VERSION 5.7 ;
  NOWIREEXTENSIONATPIN ON ;
  DIVIDERCHAR "/" ;
  BUSBITCHARS "[]" ;
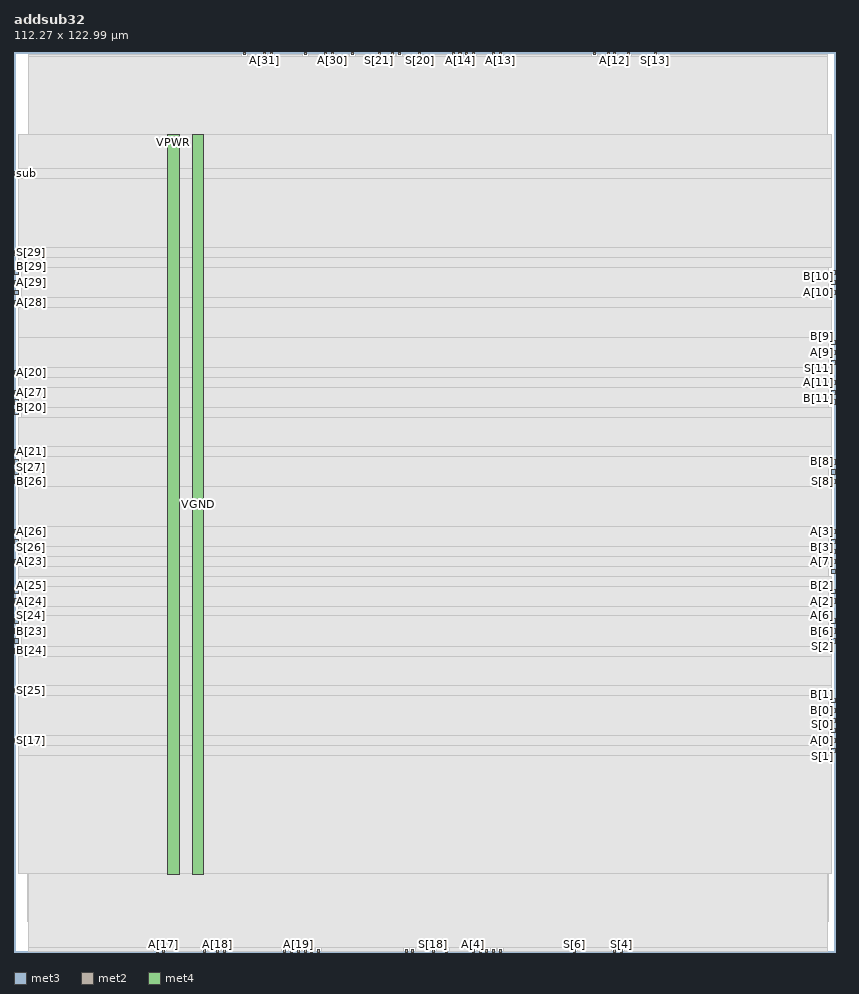
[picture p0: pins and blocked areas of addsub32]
MACRO addsub32
  CLASS BLOCK ;
  FOREIGN addsub32 ;
  ORIGIN 0.000 0.000 ;
  SIZE 112.270 BY 122.990 ;
  PIN A[0]
    DIRECTION INPUT ;
    USE SIGNAL ;
    ANTENNAGATEAREA 0.159000 ;
    PORT
      LAYER met3 ;
        RECT 111.670 28.600 112.270 29.200 ;
    END
  END A[0]
  PIN A[10]
    DIRECTION INPUT ;
    USE SIGNAL ;
    ANTENNAGATEAREA 0.213000 ;
    PORT
      LAYER met3 ;
        RECT 111.670 89.800 112.270 90.400 ;
    END
  END A[10]
  PIN A[11]
    DIRECTION INPUT ;
    USE SIGNAL ;
    ANTENNAGATEAREA 0.213000 ;
    PORT
      LAYER met3 ;
        RECT 111.670 77.560 112.270 78.160 ;
    END
  END A[11]
  PIN A[12]
    DIRECTION INPUT ;
    USE SIGNAL ;
    ANTENNAGATEAREA 0.495000 ;
    PORT
      LAYER met2 ;
        RECT 81.970 122.710 82.250 122.990 ;
    END
  END A[12]
  PIN A[13]
    DIRECTION INPUT ;
    USE SIGNAL ;
    ANTENNAGATEAREA 0.213000 ;
    PORT
      LAYER met2 ;
        RECT 66.330 122.710 66.610 122.990 ;
    END
  END A[13]
  PIN A[14]
    DIRECTION INPUT ;
    USE SIGNAL ;
    ANTENNAGATEAREA 0.213000 ;
    PORT
      LAYER met2 ;
        RECT 60.810 122.710 61.090 122.990 ;
    END
  END A[14]
  PIN A[15]
    DIRECTION INPUT ;
    USE SIGNAL ;
    ANTENNAGATEAREA 0.247500 ;
    PORT
      LAYER met2 ;
        RECT 62.650 122.710 62.930 122.990 ;
    END
  END A[15]
  PIN A[16]
    DIRECTION INPUT ;
    USE SIGNAL ;
    ANTENNAGATEAREA 0.213000 ;
    PORT
      LAYER met2 ;
        RECT 28.610 0.000 28.890 0.280 ;
    END
  END A[16]
  PIN A[17]
    DIRECTION INPUT ;
    USE SIGNAL ;
    ANTENNAGATEAREA 0.126000 ;
    PORT
      LAYER met2 ;
        RECT 20.330 0.000 20.610 0.280 ;
    END
  END A[17]
  PIN A[18]
    DIRECTION INPUT ;
    USE SIGNAL ;
    ANTENNAGATEAREA 0.213000 ;
    PORT
      LAYER met2 ;
        RECT 27.690 0.000 27.970 0.280 ;
    END
  END A[18]
  PIN A[19]
    DIRECTION INPUT ;
    USE SIGNAL ;
    ANTENNAGATEAREA 0.213000 ;
    PORT
      LAYER met2 ;
        RECT 38.730 0.000 39.010 0.280 ;
    END
  END A[19]
  PIN A[1]
    DIRECTION INPUT ;
    USE SIGNAL ;
    ANTENNAGATEAREA 0.126000 ;
    PORT
      LAYER met3 ;
        RECT 111.670 31.320 112.270 31.920 ;
    END
  END A[1]
  PIN A[20]
    DIRECTION INPUT ;
    USE SIGNAL ;
    ANTENNAGATEAREA 0.126000 ;
    PORT
      LAYER met3 ;
        RECT 0.000 78.920 0.600 79.520 ;
    END
  END A[20]
  PIN A[21]
    DIRECTION INPUT ;
    USE SIGNAL ;
    ANTENNAGATEAREA 0.213000 ;
    PORT
      LAYER met3 ;
        RECT 0.000 68.040 0.600 68.640 ;
    END
  END A[21]
  PIN A[22]
    DIRECTION INPUT ;
    USE SIGNAL ;
    ANTENNAGATEAREA 0.213000 ;
    PORT
      LAYER met2 ;
        RECT 39.650 0.000 39.930 0.280 ;
    END
  END A[22]
  PIN A[23]
    DIRECTION INPUT ;
    USE SIGNAL ;
    ANTENNAGATEAREA 0.213000 ;
    PORT
      LAYER met3 ;
        RECT 0.000 53.080 0.600 53.680 ;
    END
  END A[23]
  PIN A[24]
    DIRECTION INPUT ;
    USE SIGNAL ;
    ANTENNAGATEAREA 0.213000 ;
    PORT
      LAYER met3 ;
        RECT 0.000 47.640 0.600 48.240 ;
    END
  END A[24]
  PIN A[25]
    DIRECTION INPUT ;
    USE SIGNAL ;
    ANTENNAGATEAREA 0.126000 ;
    PORT
      LAYER met3 ;
        RECT 0.000 49.000 0.600 49.600 ;
    END
  END A[25]
  PIN A[26]
    DIRECTION INPUT ;
    USE SIGNAL ;
    ANTENNAGATEAREA 0.213000 ;
    PORT
      LAYER met3 ;
        RECT 0.000 57.160 0.600 57.760 ;
    END
  END A[26]
  PIN A[27]
    DIRECTION INPUT ;
    USE SIGNAL ;
    ANTENNAGATEAREA 0.213000 ;
    PORT
      LAYER met3 ;
        RECT 0.000 76.200 0.600 76.800 ;
    END
  END A[27]
  PIN A[28]
    DIRECTION INPUT ;
    USE SIGNAL ;
    ANTENNAGATEAREA 0.213000 ;
    PORT
      LAYER met3 ;
        RECT 0.000 88.440 0.600 89.040 ;
    END
  END A[28]
  PIN A[29]
    DIRECTION INPUT ;
    USE SIGNAL ;
    ANTENNAGATEAREA 0.213000 ;
    PORT
      LAYER met3 ;
        RECT 0.000 91.160 0.600 91.760 ;
    END
  END A[29]
  PIN A[2]
    DIRECTION INPUT ;
    USE SIGNAL ;
    ANTENNAGATEAREA 0.213000 ;
    PORT
      LAYER met3 ;
        RECT 111.670 47.640 112.270 48.240 ;
    END
  END A[2]
  PIN A[30]
    DIRECTION INPUT ;
    USE SIGNAL ;
    ANTENNAGATEAREA 0.213000 ;
    PORT
      LAYER met2 ;
        RECT 43.330 122.710 43.610 122.990 ;
    END
  END A[30]
  PIN A[31]
    DIRECTION INPUT ;
    USE SIGNAL ;
    ANTENNAGATEAREA 0.213000 ;
    PORT
      LAYER met2 ;
        RECT 34.130 122.710 34.410 122.990 ;
    END
  END A[31]
  PIN A[3]
    DIRECTION INPUT ;
    USE SIGNAL ;
    ANTENNAGATEAREA 0.213000 ;
    PORT
      LAYER met3 ;
        RECT 111.670 57.160 112.270 57.760 ;
    END
  END A[3]
  PIN A[4]
    DIRECTION INPUT ;
    USE SIGNAL ;
    ANTENNAGATEAREA 0.213000 ;
    PORT
      LAYER met2 ;
        RECT 62.650 0.000 62.930 0.280 ;
    END
  END A[4]
  PIN A[5]
    DIRECTION INPUT ;
    USE SIGNAL ;
    ANTENNAGATEAREA 0.247500 ;
    PORT
      LAYER met2 ;
        RECT 64.490 0.000 64.770 0.280 ;
    END
  END A[5]
  PIN A[6]
    DIRECTION INPUT ;
    USE SIGNAL ;
    ANTENNAGATEAREA 0.126000 ;
    PORT
      LAYER met3 ;
        RECT 111.670 44.920 112.270 45.520 ;
    END
  END A[6]
  PIN A[7]
    DIRECTION INPUT ;
    USE SIGNAL ;
    ANTENNAGATEAREA 0.213000 ;
    PORT
      LAYER met3 ;
        RECT 111.670 53.080 112.270 53.680 ;
    END
  END A[7]
  PIN A[8]
    DIRECTION INPUT ;
    USE SIGNAL ;
    ANTENNAGATEAREA 0.213000 ;
    PORT
      LAYER met3 ;
        RECT 111.670 65.320 112.270 65.920 ;
    END
  END A[8]
  PIN A[9]
    DIRECTION INPUT ;
    USE SIGNAL ;
    ANTENNAGATEAREA 0.495000 ;
    PORT
      LAYER met3 ;
        RECT 111.670 81.640 112.270 82.240 ;
    END
  END A[9]
  PIN B[0]
    DIRECTION INPUT ;
    USE SIGNAL ;
    ANTENNAGATEAREA 0.247500 ;
    PORT
      LAYER met3 ;
        RECT 111.670 32.680 112.270 33.280 ;
    END
  END B[0]
  PIN B[10]
    DIRECTION INPUT ;
    USE SIGNAL ;
    ANTENNAGATEAREA 0.247500 ;
    PORT
      LAYER met3 ;
        RECT 111.670 91.160 112.270 91.760 ;
    END
  END B[10]
  PIN B[11]
    DIRECTION INPUT ;
    USE SIGNAL ;
    ANTENNAGATEAREA 0.213000 ;
    PORT
      LAYER met3 ;
        RECT 111.670 76.200 112.270 76.800 ;
    END
  END B[11]
  PIN B[12]
    DIRECTION INPUT ;
    USE SIGNAL ;
    ANTENNAGATEAREA 0.495000 ;
    PORT
      LAYER met2 ;
        RECT 81.050 122.710 81.330 122.990 ;
    END
  END B[12]
  PIN B[13]
    DIRECTION INPUT ;
    USE SIGNAL ;
    ANTENNAGATEAREA 0.247500 ;
    PORT
      LAYER met2 ;
        RECT 65.410 122.710 65.690 122.990 ;
    END
  END B[13]
  PIN B[14]
    DIRECTION INPUT ;
    USE SIGNAL ;
    ANTENNAGATEAREA 0.213000 ;
    PORT
      LAYER met2 ;
        RECT 59.890 122.710 60.170 122.990 ;
    END
  END B[14]
  PIN B[15]
    DIRECTION INPUT ;
    USE SIGNAL ;
    ANTENNAGATEAREA 0.247500 ;
    PORT
      LAYER met2 ;
        RECT 61.730 122.710 62.010 122.990 ;
    END
  END B[15]
  PIN B[16]
    DIRECTION INPUT ;
    USE SIGNAL ;
    ANTENNAGATEAREA 0.213000 ;
    PORT
      LAYER met2 ;
        RECT 25.850 0.000 26.130 0.280 ;
    END
  END B[16]
  PIN B[17]
    DIRECTION INPUT ;
    USE SIGNAL ;
    ANTENNAGATEAREA 0.126000 ;
    PORT
      LAYER met2 ;
        RECT 19.410 0.000 19.690 0.280 ;
    END
  END B[17]
  PIN B[18]
    DIRECTION INPUT ;
    USE SIGNAL ;
    ANTENNAGATEAREA 0.213000 ;
    PORT
      LAYER met2 ;
        RECT 37.810 0.000 38.090 0.280 ;
    END
  END B[18]
  PIN B[19]
    DIRECTION INPUT ;
    USE SIGNAL ;
    ANTENNAGATEAREA 0.213000 ;
    PORT
      LAYER met2 ;
        RECT 40.570 0.000 40.850 0.280 ;
    END
  END B[19]
  PIN B[1]
    DIRECTION INPUT ;
    USE SIGNAL ;
    ANTENNAGATEAREA 0.213000 ;
    PORT
      LAYER met3 ;
        RECT 111.670 34.040 112.270 34.640 ;
    END
  END B[1]
  PIN B[20]
    DIRECTION INPUT ;
    USE SIGNAL ;
    ANTENNAGATEAREA 0.126000 ;
    PORT
      LAYER met3 ;
        RECT 0.000 74.840 0.600 75.440 ;
    END
  END B[20]
  PIN B[21]
    DIRECTION INPUT ;
    USE SIGNAL ;
    ANTENNAGATEAREA 0.213000 ;
    PORT
      LAYER met3 ;
        RECT 0.000 65.320 0.600 65.920 ;
    END
  END B[21]
  PIN B[22]
    DIRECTION INPUT ;
    USE SIGNAL ;
    ANTENNAGATEAREA 0.213000 ;
    PORT
      LAYER met2 ;
        RECT 41.490 0.000 41.770 0.280 ;
    END
  END B[22]
  PIN B[23]
    DIRECTION INPUT ;
    USE SIGNAL ;
    ANTENNAGATEAREA 0.213000 ;
    PORT
      LAYER met3 ;
        RECT 0.000 43.560 0.600 44.160 ;
    END
  END B[23]
  PIN B[24]
    DIRECTION INPUT ;
    USE SIGNAL ;
    ANTENNAGATEAREA 0.213000 ;
    PORT
      LAYER met3 ;
        RECT 0.000 40.840 0.600 41.440 ;
    END
  END B[24]
  PIN B[25]
    DIRECTION INPUT ;
    USE SIGNAL ;
    ANTENNAGATEAREA 0.126000 ;
    PORT
      LAYER met3 ;
        RECT 0.000 42.200 0.600 42.800 ;
    END
  END B[25]
  PIN B[26]
    DIRECTION INPUT ;
    USE SIGNAL ;
    ANTENNAGATEAREA 0.213000 ;
    PORT
      LAYER met3 ;
        RECT 0.000 63.960 0.600 64.560 ;
    END
  END B[26]
  PIN B[27]
    DIRECTION INPUT ;
    USE SIGNAL ;
    ANTENNAGATEAREA 0.213000 ;
    PORT
      LAYER met3 ;
        RECT 0.000 73.480 0.600 74.080 ;
    END
  END B[27]
  PIN B[28]
    DIRECTION INPUT ;
    USE SIGNAL ;
    ANTENNAGATEAREA 0.213000 ;
    PORT
      LAYER met3 ;
        RECT 0.000 89.800 0.600 90.400 ;
    END
  END B[28]
  PIN B[29]
    DIRECTION INPUT ;
    USE SIGNAL ;
    ANTENNAGATEAREA 0.213000 ;
    PORT
      LAYER met3 ;
        RECT 0.000 92.520 0.600 93.120 ;
    END
  END B[29]
  PIN B[2]
    DIRECTION INPUT ;
    USE SIGNAL ;
    ANTENNAGATEAREA 0.126000 ;
    PORT
      LAYER met3 ;
        RECT 111.670 49.000 112.270 49.600 ;
    END
  END B[2]
  PIN B[30]
    DIRECTION INPUT ;
    USE SIGNAL ;
    ANTENNAGATEAREA 0.213000 ;
    PORT
      LAYER met2 ;
        RECT 42.410 122.710 42.690 122.990 ;
    END
  END B[30]
  PIN B[31]
    DIRECTION INPUT ;
    USE SIGNAL ;
    ANTENNAGATEAREA 0.213000 ;
    PORT
      LAYER met2 ;
        RECT 35.050 122.710 35.330 122.990 ;
    END
  END B[31]
  PIN B[3]
    DIRECTION INPUT ;
    USE SIGNAL ;
    ANTENNAGATEAREA 0.126000 ;
    PORT
      LAYER met3 ;
        RECT 111.670 55.800 112.270 56.400 ;
    END
  END B[3]
  PIN B[4]
    DIRECTION INPUT ;
    USE SIGNAL ;
    ANTENNAGATEAREA 0.213000 ;
    PORT
      LAYER met2 ;
        RECT 63.570 0.000 63.850 0.280 ;
    END
  END B[4]
  PIN B[5]
    DIRECTION INPUT ;
    USE SIGNAL ;
    ANTENNAGATEAREA 0.213000 ;
    PORT
      LAYER met2 ;
        RECT 66.330 0.000 66.610 0.280 ;
    END
  END B[5]
  PIN B[6]
    DIRECTION INPUT ;
    USE SIGNAL ;
    ANTENNAGATEAREA 0.126000 ;
    PORT
      LAYER met3 ;
        RECT 111.670 43.560 112.270 44.160 ;
    END
  END B[6]
  PIN B[7]
    DIRECTION INPUT ;
    USE SIGNAL ;
    ANTENNAGATEAREA 0.213000 ;
    PORT
      LAYER met3 ;
        RECT 111.670 51.720 112.270 52.320 ;
    END
  END B[7]
  PIN B[8]
    DIRECTION INPUT ;
    USE SIGNAL ;
    ANTENNAGATEAREA 0.126000 ;
    PORT
      LAYER met3 ;
        RECT 111.670 66.680 112.270 67.280 ;
    END
  END B[8]
  PIN B[9]
    DIRECTION INPUT ;
    USE SIGNAL ;
    ANTENNAGATEAREA 0.495000 ;
    PORT
      LAYER met3 ;
        RECT 111.670 83.000 112.270 83.600 ;
    END
  END B[9]
  PIN S[0]
    DIRECTION OUTPUT ;
    USE SIGNAL ;
    ANTENNADIFFAREA 0.702900 ;
    PORT
      LAYER met3 ;
        RECT 111.670 29.960 112.270 30.560 ;
    END
  END S[0]
  PIN S[10]
    DIRECTION OUTPUT ;
    USE SIGNAL ;
    ANTENNADIFFAREA 1.336500 ;
    PORT
      LAYER met3 ;
        RECT 111.670 92.520 112.270 93.120 ;
    END
  END S[10]
  PIN S[11]
    DIRECTION OUTPUT ;
    USE SIGNAL ;
    ANTENNADIFFAREA 1.336500 ;
    PORT
      LAYER met3 ;
        RECT 111.670 80.280 112.270 80.880 ;
    END
  END S[11]
  PIN S[12]
    DIRECTION OUTPUT ;
    USE SIGNAL ;
    ANTENNADIFFAREA 1.336500 ;
    PORT
      LAYER met2 ;
        RECT 83.810 122.710 84.090 122.990 ;
    END
  END S[12]
  PIN S[13]
    DIRECTION OUTPUT ;
    USE SIGNAL ;
    ANTENNAGATEAREA 0.126000 ;
    ANTENNADIFFAREA 0.429000 ;
    PORT
      LAYER met2 ;
        RECT 87.490 122.710 87.770 122.990 ;
    END
  END S[13]
  PIN S[14]
    DIRECTION OUTPUT ;
    USE SIGNAL ;
    ANTENNADIFFAREA 1.336500 ;
    PORT
      LAYER met2 ;
        RECT 79.210 122.710 79.490 122.990 ;
    END
  END S[14]
  PIN S[15]
    DIRECTION OUTPUT ;
    USE SIGNAL ;
    ANTENNADIFFAREA 1.336500 ;
    PORT
      LAYER met2 ;
        RECT 52.530 122.710 52.810 122.990 ;
    END
  END S[15]
  PIN S[16]
    DIRECTION OUTPUT ;
    USE SIGNAL ;
    ANTENNADIFFAREA 1.336500 ;
    PORT
      LAYER met2 ;
        RECT 36.890 0.000 37.170 0.280 ;
    END
  END S[16]
  PIN S[17]
    DIRECTION OUTPUT ;
    USE SIGNAL ;
    ANTENNADIFFAREA 0.383400 ;
    PORT
      LAYER met3 ;
        RECT 0.000 28.600 0.600 29.200 ;
    END
  END S[17]
  PIN S[18]
    DIRECTION OUTPUT ;
    USE SIGNAL ;
    ANTENNADIFFAREA 0.891000 ;
    PORT
      LAYER met2 ;
        RECT 57.130 0.000 57.410 0.280 ;
    END
  END S[18]
  PIN S[19]
    DIRECTION OUTPUT ;
    USE SIGNAL ;
    ANTENNADIFFAREA 0.383400 ;
    PORT
      LAYER met2 ;
        RECT 54.370 0.000 54.650 0.280 ;
    END
  END S[19]
  PIN S[1]
    DIRECTION OUTPUT ;
    USE SIGNAL ;
    ANTENNADIFFAREA 1.336500 ;
    PORT
      LAYER met3 ;
        RECT 111.670 27.240 112.270 27.840 ;
    END
  END S[1]
  PIN S[20]
    DIRECTION OUTPUT ;
    USE SIGNAL ;
    ANTENNADIFFAREA 1.336500 ;
    PORT
      LAYER met2 ;
        RECT 55.290 122.710 55.570 122.990 ;
    END
  END S[20]
  PIN S[21]
    DIRECTION OUTPUT ;
    USE SIGNAL ;
    ANTENNADIFFAREA 1.336500 ;
    PORT
      LAYER met2 ;
        RECT 49.770 122.710 50.050 122.990 ;
    END
  END S[21]
  PIN S[22]
    DIRECTION OUTPUT ;
    USE SIGNAL ;
    ANTENNADIFFAREA 1.336500 ;
    PORT
      LAYER met2 ;
        RECT 58.970 0.000 59.250 0.280 ;
    END
  END S[22]
  PIN S[23]
    DIRECTION OUTPUT ;
    USE SIGNAL ;
    ANTENNADIFFAREA 1.336500 ;
    PORT
      LAYER met2 ;
        RECT 53.450 0.000 53.730 0.280 ;
    END
  END S[23]
  PIN S[24]
    DIRECTION OUTPUT ;
    USE SIGNAL ;
    ANTENNADIFFAREA 1.336500 ;
    PORT
      LAYER met3 ;
        RECT 0.000 44.920 0.600 45.520 ;
    END
  END S[24]
  PIN S[25]
    DIRECTION OUTPUT ;
    USE SIGNAL ;
    ANTENNADIFFAREA 1.336500 ;
    PORT
      LAYER met3 ;
        RECT 0.000 35.400 0.600 36.000 ;
    END
  END S[25]
  PIN S[26]
    DIRECTION OUTPUT ;
    USE SIGNAL ;
    ANTENNADIFFAREA 1.336500 ;
    PORT
      LAYER met3 ;
        RECT 0.000 55.800 0.600 56.400 ;
    END
  END S[26]
  PIN S[27]
    DIRECTION OUTPUT ;
    USE SIGNAL ;
    ANTENNADIFFAREA 1.336500 ;
    PORT
      LAYER met3 ;
        RECT 0.000 66.680 0.600 67.280 ;
    END
  END S[27]
  PIN S[28]
    DIRECTION OUTPUT ;
    USE SIGNAL ;
    ANTENNADIFFAREA 1.336500 ;
    PORT
      LAYER met2 ;
        RECT 39.650 122.710 39.930 122.990 ;
    END
  END S[28]
  PIN S[29]
    DIRECTION OUTPUT ;
    USE SIGNAL ;
    ANTENNADIFFAREA 0.891000 ;
    PORT
      LAYER met3 ;
        RECT 0.000 95.240 0.600 95.840 ;
    END
  END S[29]
  PIN S[2]
    DIRECTION OUTPUT ;
    USE SIGNAL ;
    ANTENNADIFFAREA 1.336500 ;
    PORT
      LAYER met3 ;
        RECT 111.670 42.200 112.270 42.800 ;
    END
  END S[2]
  PIN S[30]
    DIRECTION OUTPUT ;
    USE SIGNAL ;
    ANTENNADIFFAREA 1.336500 ;
    PORT
      LAYER met2 ;
        RECT 51.610 122.710 51.890 122.990 ;
    END
  END S[30]
  PIN S[31]
    DIRECTION OUTPUT ;
    USE SIGNAL ;
    ANTENNADIFFAREA 1.336500 ;
    PORT
      LAYER met2 ;
        RECT 46.090 122.710 46.370 122.990 ;
    END
  END S[31]
  PIN S[3]
    DIRECTION OUTPUT ;
    USE SIGNAL ;
    ANTENNADIFFAREA 0.795200 ;
    PORT
      LAYER met3 ;
        RECT 111.670 54.440 112.270 55.040 ;
    END
  END S[3]
  PIN S[4]
    DIRECTION OUTPUT ;
    USE SIGNAL ;
    ANTENNADIFFAREA 1.336500 ;
    PORT
      LAYER met2 ;
        RECT 82.890 0.000 83.170 0.280 ;
    END
  END S[4]
  PIN S[5]
    DIRECTION OUTPUT ;
    USE SIGNAL ;
    ANTENNADIFFAREA 1.336500 ;
    PORT
      LAYER met2 ;
        RECT 81.970 0.000 82.250 0.280 ;
    END
  END S[5]
  PIN S[6]
    DIRECTION OUTPUT ;
    USE SIGNAL ;
    ANTENNADIFFAREA 1.336500 ;
    PORT
      LAYER met2 ;
        RECT 76.450 0.000 76.730 0.280 ;
    END
  END S[6]
  PIN S[7]
    DIRECTION OUTPUT ;
    USE SIGNAL ;
    ANTENNADIFFAREA 1.336500 ;
    PORT
      LAYER met2 ;
        RECT 65.410 0.000 65.690 0.280 ;
    END
  END S[7]
  PIN S[8]
    DIRECTION OUTPUT ;
    USE SIGNAL ;
    ANTENNADIFFAREA 1.336500 ;
    PORT
      LAYER met3 ;
        RECT 111.670 63.960 112.270 64.560 ;
    END
  END S[8]
  PIN S[9]
    DIRECTION OUTPUT ;
    USE SIGNAL ;
    ANTENNADIFFAREA 1.336500 ;
    PORT
      LAYER met3 ;
        RECT 111.670 74.840 112.270 75.440 ;
    END
  END S[9]
  PIN VGND
    DIRECTION INOUT ;
    USE GROUND ;
    PORT
      LAYER met4 ;
        RECT 24.340 10.640 25.940 111.760 ;
    END
  END VGND
  PIN VPWR
    DIRECTION INOUT ;
    USE POWER ;
    PORT
      LAYER met4 ;
        RECT 21.040 10.640 22.640 111.760 ;
    END
  END VPWR
  PIN carryOut
    DIRECTION OUTPUT ;
    USE SIGNAL ;
    ANTENNADIFFAREA 1.782000 ;
    PORT
      LAYER met2 ;
        RECT 31.370 122.710 31.650 122.990 ;
    END
  END carryOut
  PIN sub
    DIRECTION INPUT ;
    USE SIGNAL ;
    ANTENNAGATEAREA 0.742500 ;
    PORT
      LAYER met3 ;
        RECT 0.000 106.120 0.600 106.720 ;
    END
  END sub
  OBS
      LAYER nwell ;
        RECT 5.330 10.795 106.910 111.710 ;
      LAYER li1 ;
        RECT 5.520 10.795 106.720 111.605 ;
      LAYER met1 ;
        RECT 1.910 4.120 111.250 111.760 ;
      LAYER met2 ;
        RECT 1.930 122.430 31.090 122.710 ;
        RECT 31.930 122.430 33.850 122.710 ;
        RECT 34.690 122.430 34.770 122.710 ;
        RECT 35.610 122.430 39.370 122.710 ;
        RECT 40.210 122.430 42.130 122.710 ;
        RECT 42.970 122.430 43.050 122.710 ;
        RECT 43.890 122.430 45.810 122.710 ;
        RECT 46.650 122.430 49.490 122.710 ;
        RECT 50.330 122.430 51.330 122.710 ;
        RECT 52.170 122.430 52.250 122.710 ;
        RECT 53.090 122.430 55.010 122.710 ;
        RECT 55.850 122.430 59.610 122.710 ;
        RECT 60.450 122.430 60.530 122.710 ;
        RECT 61.370 122.430 61.450 122.710 ;
        RECT 62.290 122.430 62.370 122.710 ;
        RECT 63.210 122.430 65.130 122.710 ;
        RECT 65.970 122.430 66.050 122.710 ;
        RECT 66.890 122.430 78.930 122.710 ;
        RECT 79.770 122.430 80.770 122.710 ;
        RECT 81.610 122.430 81.690 122.710 ;
        RECT 82.530 122.430 83.530 122.710 ;
        RECT 84.370 122.430 87.210 122.710 ;
        RECT 88.050 122.430 111.230 122.710 ;
        RECT 1.930 0.560 111.230 122.430 ;
        RECT 1.930 0.070 19.130 0.560 ;
        RECT 19.970 0.070 20.050 0.560 ;
        RECT 20.890 0.070 25.570 0.560 ;
        RECT 26.410 0.070 27.410 0.560 ;
        RECT 28.250 0.070 28.330 0.560 ;
        RECT 29.170 0.070 36.610 0.560 ;
        RECT 37.450 0.070 37.530 0.560 ;
        RECT 38.370 0.070 38.450 0.560 ;
        RECT 39.290 0.070 39.370 0.560 ;
        RECT 40.210 0.070 40.290 0.560 ;
        RECT 41.130 0.070 41.210 0.560 ;
        RECT 42.050 0.070 53.170 0.560 ;
        RECT 54.010 0.070 54.090 0.560 ;
        RECT 54.930 0.070 56.850 0.560 ;
        RECT 57.690 0.070 58.690 0.560 ;
        RECT 59.530 0.070 62.370 0.560 ;
        RECT 63.210 0.070 63.290 0.560 ;
        RECT 64.130 0.070 64.210 0.560 ;
        RECT 65.050 0.070 65.130 0.560 ;
        RECT 65.970 0.070 66.050 0.560 ;
        RECT 66.890 0.070 76.170 0.560 ;
        RECT 77.010 0.070 81.690 0.560 ;
        RECT 82.530 0.070 82.610 0.560 ;
        RECT 83.450 0.070 111.230 0.560 ;
      LAYER met3 ;
        RECT 0.600 107.120 111.670 111.685 ;
        RECT 1.000 105.720 111.670 107.120 ;
        RECT 0.600 96.240 111.670 105.720 ;
        RECT 1.000 94.840 111.670 96.240 ;
        RECT 0.600 93.520 111.670 94.840 ;
        RECT 1.000 89.400 111.270 93.520 ;
        RECT 1.000 88.040 111.670 89.400 ;
        RECT 0.600 84.000 111.670 88.040 ;
        RECT 0.600 79.920 111.270 84.000 ;
        RECT 1.000 79.880 111.270 79.920 ;
        RECT 1.000 78.560 111.670 79.880 ;
        RECT 1.000 78.520 111.270 78.560 ;
        RECT 0.600 77.200 111.270 78.520 ;
        RECT 1.000 74.440 111.270 77.200 ;
        RECT 1.000 73.080 111.670 74.440 ;
        RECT 0.600 69.040 111.670 73.080 ;
        RECT 1.000 67.680 111.670 69.040 ;
        RECT 1.000 63.560 111.270 67.680 ;
        RECT 0.600 58.160 111.670 63.560 ;
        RECT 1.000 55.400 111.270 58.160 ;
        RECT 0.600 54.080 111.270 55.400 ;
        RECT 1.000 52.680 111.270 54.080 ;
        RECT 0.600 51.320 111.270 52.680 ;
        RECT 0.600 50.000 111.670 51.320 ;
        RECT 1.000 47.240 111.270 50.000 ;
        RECT 0.600 45.920 111.670 47.240 ;
        RECT 1.000 41.800 111.270 45.920 ;
        RECT 1.000 40.440 111.670 41.800 ;
        RECT 0.600 36.400 111.670 40.440 ;
        RECT 1.000 35.040 111.670 36.400 ;
        RECT 1.000 35.000 111.270 35.040 ;
        RECT 0.600 29.600 111.270 35.000 ;
        RECT 1.000 28.200 111.270 29.600 ;
        RECT 0.600 26.840 111.270 28.200 ;
        RECT 0.600 10.715 111.670 26.840 ;
  END
END addsub32
END LIBRARY

